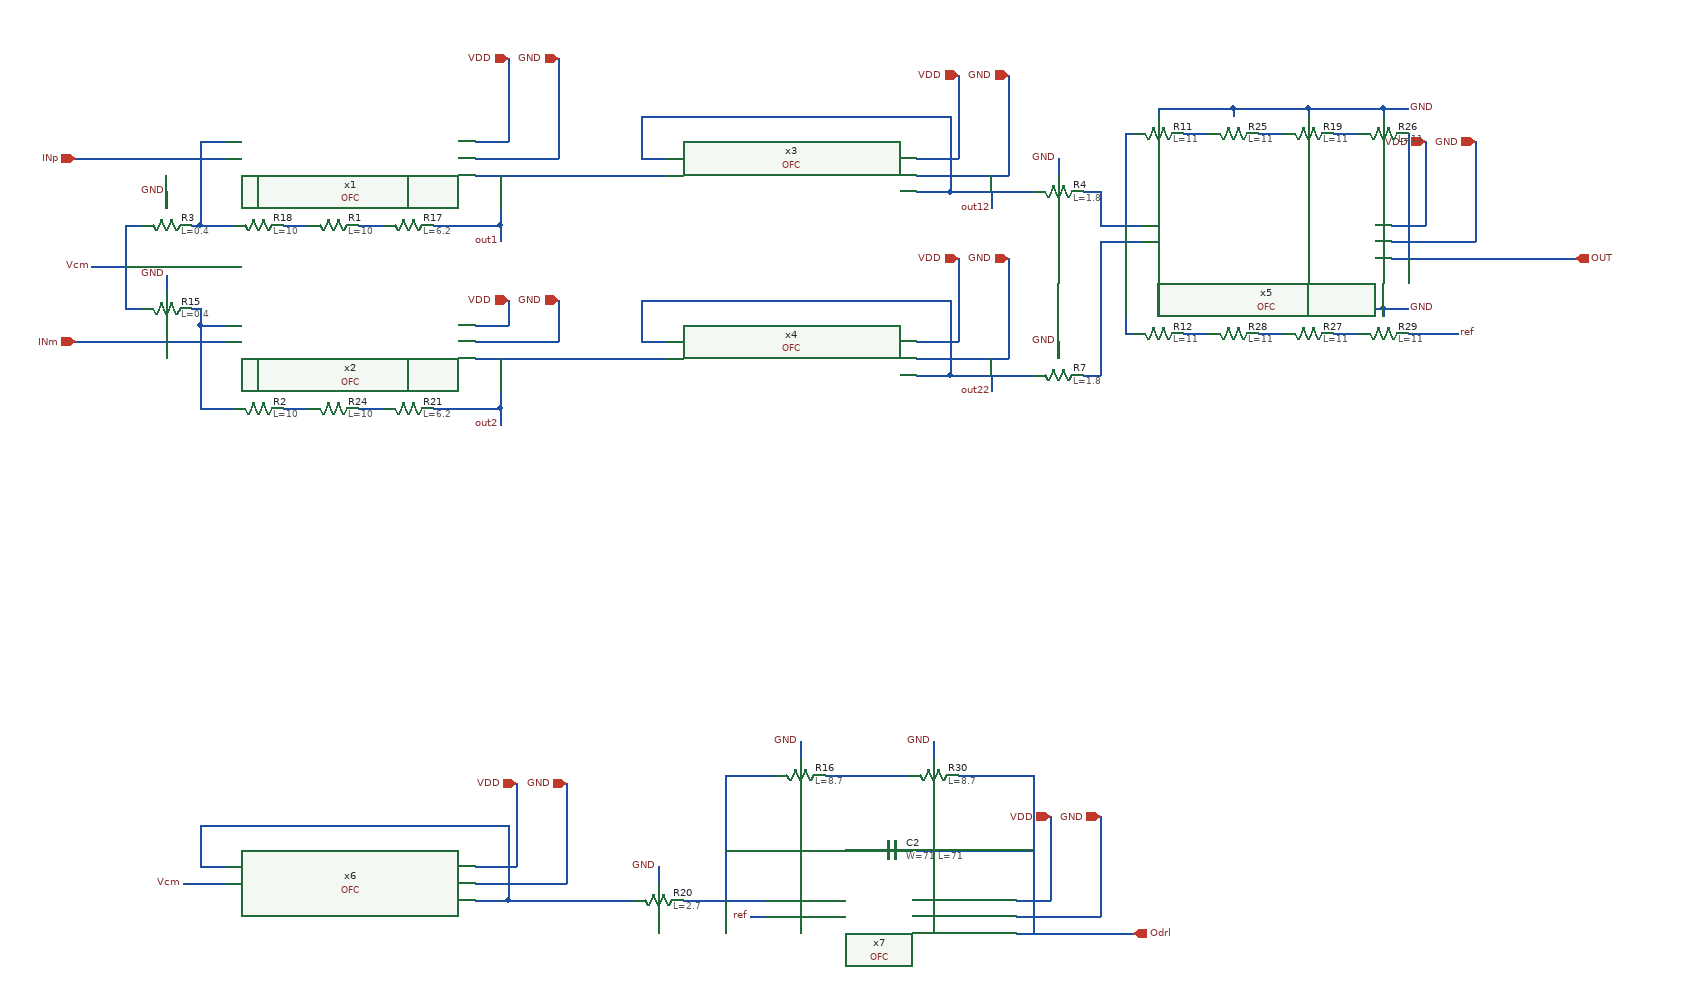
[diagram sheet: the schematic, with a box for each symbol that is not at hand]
v {xschem version=3.4.5 file_version=1.2
}
G {}
K {}
V {}
S {}
E {}
N -390 -250 -310 -250 {
lab=out1}
N -390 -30 -310 -30 {
lab=out2}
N 370 -170 410 -170 {
lab=#net1}
N 370 -190 410 -190 {
lab=#net2}
N -390 -290 -350 -290 {
lab=VDD}
N -350 -390 -350 -290 {
lab=VDD}
N -390 -270 -310 -270 {
lab=GND}
N -310 -270 -290 -270 {
lab=GND}
N -290 -390 -290 -270 {
lab=GND}
N -390 -70 -350 -70 {
lab=VDD}
N -350 -100 -350 -70 {
lab=VDD}
N -390 -50 -290 -50 {
lab=GND}
N -290 -100 -290 -50 {
lab=GND}
N -790 -270 -690 -270 {
lab=INp}
N -790 -50 -690 -50 {
lab=INm}
N -720 -290 -690 -290 {
lab=#net3}
N -720 -290 -720 -230 {
lab=#net3}
N -360 -250 -360 -230 {
lab=out1}
N -720 -70 -690 -70 {
lab=#net4}
N -720 -70 -720 -20 {
lab=#net4}
N -720 -20 -720 -10 {
lab=#net4}
N 710 -190 750 -190 {
lab=VDD}
N 750 -290 750 -190 {
lab=VDD}
N 710 -170 790 -170 {
lab=GND}
N 790 -170 810 -170 {
lab=GND}
N 810 -290 810 -170 {
lab=GND}
N 710 -150 850 -150 {
lab=#net5}
N -360 -230 -360 -210 {
lab=out1}
N -360 -30 -360 -10 {
lab=out2}
N -360 -10 -360 10 {
lab=out2}
N 850 -150 900 -150 {
lab=#net5}
N 900 -150 930 -150 {
lab=#net5}
N -720 -230 -720 -210 {
lab=#net3}
N -720 -10 -720 10 {
lab=#net4}
N -310 -250 -300 -250 {
lab=out1}
N -310 -30 -300 -30 {
lab=out2}
N 390 -170 390 -60 {
lab=#net1}
N 390 -300 390 -190 {
lab=#net2}
N 730 -300 730 -150 {
lab=#net5}
N -300 -250 -160 -250 {
lab=out1}
N -300 -30 -160 -30 {
lab=out2}
N -190 -270 -160 -270 {
lab=out12}
N -190 -320 -190 -270 {
lab=out12}
N -190 -320 180 -320 {
lab=out12}
N 180 -320 180 -230 {
lab=out12}
N 140 -230 180 -230 {
lab=out12}
N -190 -50 -160 -50 {
lab=out22}
N -190 -100 -190 -50 {
lab=out22}
N -190 -100 180 -100 {
lab=out22}
N 180 -100 180 -10 {
lab=out22}
N 140 -10 180 -10 {
lab=out22}
N 150 -270 190 -270 {
lab=VDD}
N 190 -370 190 -270 {
lab=VDD}
N 150 -250 230 -250 {
lab=GND}
N 230 -250 250 -250 {
lab=GND}
N 250 -370 250 -250 {
lab=GND}
N 140 -270 150 -270 {
lab=VDD}
N 140 -250 150 -250 {
lab=GND}
N 150 -50 190 -50 {
lab=VDD}
N 190 -150 190 -50 {
lab=VDD}
N 150 -30 230 -30 {
lab=GND}
N 230 -30 250 -30 {
lab=GND}
N 250 -150 250 -30 {
lab=GND}
N 140 -50 150 -50 {
lab=VDD}
N 140 -30 150 -30 {
lab=GND}
N 360 -230 360 -190 {
lab=#net2}
N 360 -190 370 -190 {
lab=#net2}
N 360 -170 370 -170 {
lab=#net1}
N 360 -170 360 -10 {
lab=#net1}
N 180 -230 280 -230 {
lab=out12}
N 340 -230 360 -230 {
lab=#net2}
N 340 -10 360 -10 {
lab=#net1}
N 180 -10 280 -10 {
lab=out22}
N -360 -210 -360 -190 {
lab=out1}
N -360 10 -360 30 {
lab=out2}
N 230 -230 230 -210 {
lab=out12}
N 230 -10 230 10 {
lab=out22}
N -720 -90 -720 -70 {
lab=#net4}
N -730 -90 -720 -90 {
lab=#net4}
N -730 -190 -720 -190 {
lab=#net3}
N -720 -210 -720 -190 {
lab=#net3}
N -810 -190 -790 -190 {
lab=Vcm}
N -810 -190 -810 -90 {
lab=Vcm}
N -810 -90 -790 -90 {
lab=Vcm}
N -870 -270 -790 -270 {
lab=INp}
N -870 -50 -790 -50 {
lab=INm}
N -850 -140 -810 -140 {
lab=Vcm}
N 260 620 300 620 {
lab=VDD}
N 300 520 300 620 {
lab=VDD}
N 260 640 340 640 {
lab=GND}
N 340 640 360 640 {
lab=GND}
N 360 520 360 640 {
lab=GND}
N 260 660 400 660 {
lab=#net6}
N 280 530 280 660 {
lab=#net6}
N -60 640 -40 640 {
lab=ref}
N -140 620 -40 620 {
lab=#net7}
N -90 530 -90 620 {
lab=#net7}
N -250 620 -200 620 {
lab=#net8}
N 280 470 280 530 {
lab=#net6}
N -90 470 -90 530 {
lab=#net7}
N -720 580 -690 580 {
lab=#net8}
N -720 530 -720 580 {
lab=#net8}
N -720 530 -350 530 {
lab=#net8}
N -350 530 -350 620 {
lab=#net8}
N -390 620 -350 620 {
lab=#net8}
N -380 580 -340 580 {
lab=VDD}
N -340 480 -340 580 {
lab=VDD}
N -380 600 -300 600 {
lab=GND}
N -300 600 -280 600 {
lab=GND}
N -280 480 -280 600 {
lab=GND}
N -390 580 -380 580 {
lab=VDD}
N -390 600 -380 600 {
lab=GND}
N -350 620 -250 620 {
lab=#net8}
N -740 600 -690 600 {
lab=Vcm}
N -90 560 80 560 {
lab=#net7}
N 140 560 280 560 {
lab=#net6}
N -760 -230 -760 -210 {
lab=GND}
N -760 -130 -760 -110 {
lab=GND}
N -170 580 -170 600 {
lab=GND}
N -720 -190 -680 -190 {
lab=#net3}
N -620 -190 -590 -190 {
lab=#net9}
N -530 -190 -500 -190 {
lab=#net10}
N -440 -190 -360 -190 {
lab=out1}
N -360 -190 -360 -170 {
lab=out1}
N -650 -220 -650 -210 {
lab=GND}
N -650 -220 -560 -220 {
lab=GND}
N -560 -220 -560 -210 {
lab=GND}
N -560 -220 -560 -210 {
lab=GND}
N -560 -220 -470 -220 {
lab=GND}
N -470 -220 -470 -210 {
lab=GND}
N -470 -220 -450 -220 {
lab=GND}
N -720 30 -680 30 {
lab=#net4}
N -620 30 -590 30 {
lab=#net11}
N -530 30 -500 30 {
lab=#net12}
N -440 30 -360 30 {
lab=out2}
N -650 0 -650 10 {
lab=GND}
N -650 0 -560 0 {
lab=GND}
N -560 0 -560 10 {
lab=GND}
N -560 0 -560 10 {
lab=GND}
N -560 0 -470 0 {
lab=GND}
N -470 0 -470 10 {
lab=GND}
N -470 0 -450 0 {
lab=GND}
N -720 20 -720 30 {
lab=#net4}
N -720 10 -720 20 {
lab=#net4}
N -360 30 -360 50 {
lab=out2}
N 310 -270 310 -250 {
lab=GND}
N 310 -50 310 -30 {
lab=GND}
N 460 -300 490 -300 {
lab=#net13}
N 550 -300 580 -300 {
lab=#net14}
N 430 -330 430 -320 {
lab=GND}
N 430 -330 520 -330 {
lab=GND}
N 520 -330 520 -320 {
lab=GND}
N 520 -330 520 -320 {
lab=GND}
N 520 -330 610 -330 {
lab=GND}
N 610 -330 610 -320 {
lab=GND}
N 610 -330 630 -330 {
lab=GND}
N 390 -300 400 -300 {
lab=#net2}
N 640 -300 670 -300 {
lab=#net15}
N 700 -330 700 -320 {
lab=GND}
N 630 -330 700 -330 {
lab=GND}
N 700 -330 730 -330 {
lab=GND}
N 460 -60 490 -60 {
lab=#net16}
N 550 -60 580 -60 {
lab=#net17}
N 430 -90 430 -80 {
lab=GND}
N 430 -90 520 -90 {
lab=GND}
N 520 -90 520 -80 {
lab=GND}
N 520 -90 520 -80 {
lab=GND}
N 520 -90 610 -90 {
lab=GND}
N 610 -90 610 -80 {
lab=GND}
N 610 -90 630 -90 {
lab=GND}
N 390 -60 400 -60 {
lab=#net1}
N 640 -60 670 -60 {
lab=#net18}
N 700 -90 700 -80 {
lab=GND}
N 630 -90 700 -90 {
lab=GND}
N 700 -90 730 -90 {
lab=GND}
N 730 -60 790 -60 {
lab=ref}
N -90 470 -30 470 {
lab=#net7}
N 190 470 280 470 {
lab=#net6}
N 30 470 130 470 {
lab=#net19}
N 0 430 0 450 {
lab=GND}
N 160 430 160 450 {
lab=GND}
C {devices/iopin.sym} -350 -390 0 0 {name=p13 lab=VDD}
C {devices/iopin.sym} -350 -100 0 0 {name=p14 lab=VDD}
C {devices/iopin.sym} -290 -390 0 0 {name=p15 lab=GND}
C {devices/iopin.sym} -290 -100 0 0 {name=p16 lab=GND}
C {devices/iopin.sym} 750 -290 0 0 {name=p10 lab=VDD}
C {devices/iopin.sym} 810 -290 0 0 {name=p17 lab=GND}
C {devices/lab_pin.sym} -360 -170 0 0 {name=p18 sig_type=std_logic lab=out1}
C {devices/lab_pin.sym} -360 50 0 0 {name=p19 sig_type=std_logic lab=out2}
C {devices/lab_pin.sym} 790 -60 0 1 {name=p25 sig_type=std_logic lab=ref}
C {devices/iopin.sym} 190 -370 0 0 {name=p28 lab=VDD}
C {devices/iopin.sym} 250 -370 0 0 {name=p29 lab=GND}
C {devices/iopin.sym} 190 -150 0 0 {name=p30 lab=VDD}
C {devices/iopin.sym} 250 -150 0 0 {name=p31 lab=GND}
C {devices/lab_pin.sym} 230 -210 0 0 {name=p32 sig_type=std_logic lab=out12}
C {devices/lab_pin.sym} 230 10 0 0 {name=p33 sig_type=std_logic lab=out22}
C {devices/lab_pin.sym} -850 -140 0 0 {name=p48 sig_type=std_logic lab=Vcm}
C {devices/iopin.sym} 300 520 0 0 {name=p49 lab=VDD}
C {devices/iopin.sym} 360 520 0 0 {name=p50 lab=GND}
C {devices/lab_pin.sym} -60 640 0 0 {name=p51 sig_type=std_logic lab=ref}
C {devices/lab_pin.sym} -740 600 0 0 {name=p52 sig_type=std_logic lab=Vcm}
C {devices/iopin.sym} -340 480 0 0 {name=p53 lab=VDD}
C {devices/iopin.sym} -280 480 0 0 {name=p54 lab=GND}
C {sky130_fd_pr/res_high_po_0p35.sym} -760 -190 1 0 {name=R3
L=0.4
model=res_high_po_0p35
spiceprefix=X
mult=1}
C {devices/lab_pin.sym} -760 -230 0 0 {name=p63 sig_type=std_logic lab=GND}
C {sky130_fd_pr/res_high_po_0p35.sym} -760 -90 1 0 {name=R15
L=0.4
model=res_high_po_0p35
spiceprefix=X
mult=1}
C {devices/lab_pin.sym} -760 -130 0 0 {name=p64 sig_type=std_logic lab=GND}
C {sky130_fd_pr/res_xhigh_po_0p35.sym} -650 -190 1 0 {name=R18
L=10
model=res_xhigh_po_0p35
spiceprefix=X
mult=1}
C {sky130_fd_pr/res_high_po_5p73.sym} -170 620 1 0 {name=R20
L=2.7
model=res_high_po_5p73
spiceprefix=X
mult=1}
C {devices/lab_pin.sym} -170 580 0 0 {name=p20 sig_type=std_logic lab=GND}
C {sky130_fd_pr/res_xhigh_po_0p35.sym} -470 -190 1 0 {name=R17
L=6.2
model=res_xhigh_po_0p35
spiceprefix=X
mult=1}
C {sky130_fd_pr/res_xhigh_po_0p35.sym} -560 -190 1 0 {name=R1
L=10
model=res_xhigh_po_0p35
spiceprefix=X
mult=1}
C {devices/lab_pin.sym} -450 -220 0 1 {name=p21 sig_type=std_logic lab=GND}
C {sky130_fd_pr/res_xhigh_po_0p35.sym} -650 30 1 0 {name=R2
L=10
model=res_xhigh_po_0p35
spiceprefix=X
mult=1}
C {sky130_fd_pr/res_xhigh_po_0p35.sym} -470 30 1 0 {name=R21
L=6.2
model=res_xhigh_po_0p35
spiceprefix=X
mult=1}
C {sky130_fd_pr/res_xhigh_po_0p35.sym} -560 30 1 0 {name=R24
L=10
model=res_xhigh_po_0p35
spiceprefix=X
mult=1}
C {devices/lab_pin.sym} -450 0 0 1 {name=p24 sig_type=std_logic lab=GND}
C {sky130_fd_pr/res_xhigh_po_0p35.sym} 310 -230 1 0 {name=R4
L=1.8
model=res_xhigh_po_0p35
spiceprefix=X
mult=1}
C {sky130_fd_pr/res_xhigh_po_0p35.sym} 310 -10 1 0 {name=R7
L=1.8
model=res_xhigh_po_0p35
spiceprefix=X
mult=1}
C {devices/lab_pin.sym} 310 -270 0 0 {name=p26 sig_type=std_logic lab=GND}
C {devices/lab_pin.sym} 310 -50 0 0 {name=p27 sig_type=std_logic lab=GND}
C {sky130_fd_pr/res_xhigh_po_0p35.sym} 430 -300 1 0 {name=R11
L=11
model=res_xhigh_po_0p35
spiceprefix=X
mult=1}
C {sky130_fd_pr/res_xhigh_po_0p35.sym} 610 -300 1 0 {name=R19
L=11
model=res_xhigh_po_0p35
spiceprefix=X
mult=1}
C {sky130_fd_pr/res_xhigh_po_0p35.sym} 520 -300 1 0 {name=R25
L=11
model=res_xhigh_po_0p35
spiceprefix=X
mult=1}
C {devices/lab_pin.sym} 730 -330 0 1 {name=p38 sig_type=std_logic lab=GND}
C {sky130_fd_pr/res_xhigh_po_0p35.sym} 700 -300 1 0 {name=R26
L=11
model=res_xhigh_po_0p35
spiceprefix=X
mult=1}
C {sky130_fd_pr/res_xhigh_po_0p35.sym} 430 -60 1 0 {name=R12
L=11
model=res_xhigh_po_0p35
spiceprefix=X
mult=1}
C {sky130_fd_pr/res_xhigh_po_0p35.sym} 610 -60 1 0 {name=R27
L=11
model=res_xhigh_po_0p35
spiceprefix=X
mult=1}
C {sky130_fd_pr/res_xhigh_po_0p35.sym} 520 -60 1 0 {name=R28
L=11
model=res_xhigh_po_0p35
spiceprefix=X
mult=1}
C {devices/lab_pin.sym} 730 -90 0 1 {name=p40 sig_type=std_logic lab=GND}
C {sky130_fd_pr/res_xhigh_po_0p35.sym} 700 -60 1 0 {name=R29
L=11
model=res_xhigh_po_0p35
spiceprefix=X
mult=1}
C {sky130_fd_pr/res_xhigh_po_0p35.sym} 0 470 1 0 {name=R16
L=8.7
model=res_xhigh_po_0p35
spiceprefix=X
mult=1}
C {sky130_fd_pr/res_xhigh_po_0p35.sym} 160 470 1 0 {name=R30
L=8.7
model=res_xhigh_po_0p35
spiceprefix=X
mult=1}
C {sky130_fd_pr/cap_mim_m3_1.sym} 110 560 3 0 {name=C2 model=cap_mim_m3_1 W=71 L=71 MF=1 spiceprefix=X}
C {devices/lab_pin.sym} 0 430 0 0 {name=p62 sig_type=std_logic lab=GND}
C {devices/lab_pin.sym} 160 430 0 0 {name=p69 sig_type=std_logic lab=GND}
C {OFC.sym} -540 -270 0 0 {name=x1}
C {OFC.sym} -540 -50 0 0 {name=x2}
C {OFC.sym} -10 -250 0 0 {name=x3}
C {OFC.sym} -10 -30 0 0 {name=x4}
C {OFC.sym} 560 -170 0 0 {name=x5}
C {OFC.sym} -540 600 0 0 {name=x6}
C {OFC.sym} 110 640 0 0 {name=x7}
C {devices/ipin.sym} -870 -270 0 0 {name=p1 lab=INp}
C {devices/ipin.sym} -870 -50 0 0 {name=p2 lab=INm}
C {devices/opin.sym} 400 660 0 0 {name=p3 lab=Odrl}
C {devices/opin.sym} 930 -150 0 0 {name=p4 lab=OUT}
